VERSION 5.8 ;
BUSBITCHARS "[]" ;
DIVIDERCHAR "/" ;
UNITS
    DATABASE MICRONS 1000 ;
END UNITS

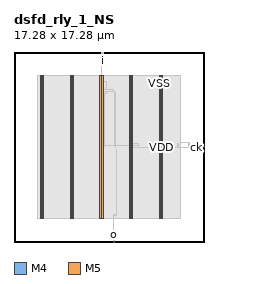
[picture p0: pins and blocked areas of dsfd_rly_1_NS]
MACRO dsfd_rly_1_NS
  FOREIGN dsfd_rly_1_NS 0 0 ;
  CLASS BLOCK ;
  SIZE 17.28 BY 17.28 ;
  PIN ck
    DIRECTION INPUT ;
    USE SIGNAL ;
    PORT
      LAYER M4 ;
        RECT  17.196 8.592 17.28 8.616 ;
    END
  END ck
  PIN i
    DIRECTION INPUT ;
    USE SIGNAL ;
    PORT
      LAYER M5 ;
        RECT  8.112 17.196 8.136 17.28 ;
    END
  END i
  PIN o
    DIRECTION OUTPUT ;
    USE SIGNAL ;
    PORT
      LAYER M5 ;
        RECT  9.072 0 9.096 0.084 ;
    END
  END o
  PIN rs
    DIRECTION INPUT ;
    USE SIGNAL ;
    PORT
      LAYER M4 ;
        RECT  17.196 8.688 17.28 8.712 ;
    END
  END rs
  PIN VDD
    DIRECTION INOUT ;
    USE POWER ;
    PORT
      LAYER M5 ;
        RECT  13.392 2.151 13.512 15.129 ;
        RECT  10.692 2.151 10.812 15.129 ;
        RECT  7.992 2.151 8.112 15.129 ;
        RECT  5.292 2.151 5.412 15.129 ;
        RECT  2.592 2.151 2.712 15.129 ;
    END
  END VDD
  PIN VSS
    DIRECTION INOUT ;
    USE GROUND ;
    PORT
      LAYER M5 ;
        RECT  13.2 2.137 13.32 15.143 ;
        RECT  10.5 2.137 10.62 15.143 ;
        RECT  7.8 2.137 7.92 15.143 ;
        RECT  5.1 2.137 5.22 15.143 ;
        RECT  2.4 2.137 2.52 15.143 ;
    END
  END VSS
  OBS
    LAYER RVTN ;
     RECT  2.16 2.16 15.12 2.295 ;
     RECT  2.16 2.565 15.12 2.835 ;
     RECT  2.16 3.105 15.12 3.375 ;
     RECT  2.16 3.645 15.12 3.915 ;
     RECT  2.16 4.185 15.12 4.455 ;
     RECT  2.16 4.725 15.12 4.995 ;
     RECT  2.16 5.265 15.12 5.535 ;
     RECT  2.16 5.805 15.12 6.075 ;
     RECT  2.16 6.345 15.12 6.615 ;
     RECT  2.16 6.885 15.12 7.155 ;
     RECT  2.16 7.425 15.12 7.695 ;
     RECT  2.16 7.965 15.12 8.235 ;
     RECT  2.16 8.505 15.12 8.775 ;
     RECT  2.16 9.045 15.12 9.315 ;
     RECT  2.16 9.585 15.12 9.855 ;
     RECT  2.16 10.125 15.12 10.395 ;
     RECT  2.16 10.665 15.12 10.935 ;
     RECT  2.16 11.205 15.12 11.475 ;
     RECT  2.16 11.745 15.12 12.015 ;
     RECT  2.16 12.285 15.12 12.555 ;
     RECT  2.16 12.825 15.12 13.095 ;
     RECT  2.16 13.365 15.12 13.635 ;
     RECT  2.16 13.905 15.12 14.175 ;
     RECT  2.16 14.445 15.12 14.715 ;
     RECT  2.16 14.985 15.12 15.12 ;
    LAYER RVTP ;
     RECT  2.16 2.295 15.12 2.565 ;
     RECT  2.16 2.835 15.12 3.105 ;
     RECT  2.16 3.375 15.12 3.645 ;
     RECT  2.16 3.915 15.12 4.185 ;
     RECT  2.16 4.455 15.12 4.725 ;
     RECT  2.16 4.995 15.12 5.265 ;
     RECT  2.16 5.535 15.12 5.805 ;
     RECT  2.16 6.075 15.12 6.345 ;
     RECT  2.16 6.615 15.12 6.885 ;
     RECT  2.16 7.155 15.12 7.425 ;
     RECT  2.16 7.695 15.12 7.965 ;
     RECT  2.16 8.235 15.12 8.505 ;
     RECT  2.16 8.775 15.12 9.045 ;
     RECT  2.16 9.315 15.12 9.585 ;
     RECT  2.16 9.855 15.12 10.125 ;
     RECT  2.16 10.395 15.12 10.665 ;
     RECT  2.16 10.935 15.12 11.205 ;
     RECT  2.16 11.475 15.12 11.745 ;
     RECT  2.16 12.015 15.12 12.285 ;
     RECT  2.16 12.555 15.12 12.825 ;
     RECT  2.16 13.095 15.12 13.365 ;
     RECT  2.16 13.635 15.12 13.905 ;
     RECT  2.16 14.175 15.12 14.445 ;
     RECT  2.16 14.715 15.12 14.985 ;
    LAYER M1 ;
     RECT  2.16 2.151 15.12 15.129 ;
    LAYER M2 ;
     RECT  2.16 2.151 15.12 15.129 ;
     RECT  15.12 9.018 15.935 9.036 ;
    LAYER M3 ;
     RECT  9.036 0.091 9.054 2.371 ;
     RECT  2.415 2.143 2.505 2.413 ;
     RECT  5.115 2.143 5.205 2.413 ;
     RECT  7.815 2.143 7.905 2.413 ;
     RECT  10.515 2.143 10.605 2.413 ;
     RECT  13.215 2.143 13.305 2.413 ;
     RECT  9.036 2.371 9.342 2.489 ;
     RECT  9.324 2.489 9.342 8.429 ;
     RECT  13.215 2.413 13.497 8.581 ;
     RECT  13.104 8.581 13.497 8.621 ;
     RECT  10.515 2.413 10.797 8.779 ;
     RECT  9.216 8.581 9.234 8.851 ;
     RECT  10.515 8.779 11.286 8.969 ;
     RECT  14.904 8.707 14.922 8.969 ;
     RECT  13.212 8.621 13.497 9.005 ;
     RECT  15.912 8.683 15.93 9.041 ;
     RECT  9.144 8.851 9.234 11.272 ;
     RECT  7.815 2.413 8.097 13.099 ;
     RECT  7.815 13.099 8.19 13.531 ;
     RECT  9.108 11.272 9.234 13.559 ;
     RECT  9.108 13.559 9.126 13.667 ;
     RECT  7.815 13.531 8.37 13.675 ;
     RECT  7.815 13.675 9.054 13.829 ;
     RECT  7.815 13.829 8.37 14.639 ;
     RECT  2.415 2.413 2.697 14.867 ;
     RECT  5.115 2.413 5.397 14.867 ;
     RECT  10.515 8.969 10.797 14.867 ;
     RECT  13.215 9.005 13.497 14.867 ;
     RECT  7.815 14.639 8.154 14.909 ;
     RECT  2.415 14.867 2.505 15.137 ;
     RECT  5.115 14.867 5.205 15.137 ;
     RECT  7.815 14.909 7.974 15.137 ;
     RECT  10.515 14.867 10.605 15.137 ;
     RECT  13.215 14.867 13.305 15.137 ;
     RECT  7.956 15.137 7.974 17.261 ;
    LAYER M4 ;
     RECT  2.408 2.148 2.512 15.132 ;
     RECT  2.512 2.418 2.704 14.862 ;
     RECT  5.108 2.148 5.212 15.132 ;
     RECT  5.212 2.418 5.404 14.862 ;
     RECT  7.808 2.148 7.912 15.132 ;
     RECT  7.944 17.232 8.005 17.256 ;
     RECT  8.005 17.136 8.064 17.256 ;
     RECT  7.912 2.418 8.104 14.862 ;
     RECT  8.064 17.136 8.147 17.16 ;
     RECT  8.104 13.104 8.245 13.128 ;
     RECT  9.025 0.096 9.109 0.12 ;
     RECT  8.104 8.736 10.508 8.76 ;
     RECT  10.508 2.148 10.612 15.132 ;
     RECT  10.612 2.418 10.804 14.862 ;
     RECT  10.804 8.592 13.208 8.616 ;
     RECT  13.208 2.148 13.312 15.132 ;
     RECT  13.312 2.418 13.504 14.862 ;
     RECT  13.504 8.592 15.901 8.616 ;
     RECT  15.901 8.592 17.244 8.712 ;
    LAYER M5 ;
     RECT  9.072 0.016 9.096 0.131 ;
     RECT  2.4 2.137 2.52 2.151 ;
     RECT  5.1 2.137 5.22 2.151 ;
     RECT  7.8 2.137 7.92 2.151 ;
     RECT  10.5 2.137 10.62 2.151 ;
     RECT  13.2 2.137 13.32 2.151 ;
     RECT  7.8 2.151 8.112 8.725 ;
     RECT  7.8 8.725 8.232 13.139 ;
     RECT  2.4 2.151 2.712 15.129 ;
     RECT  5.1 2.151 5.412 15.129 ;
     RECT  7.8 13.139 8.112 15.129 ;
     RECT  10.5 2.151 10.812 15.129 ;
     RECT  13.2 2.151 13.512 15.129 ;
     RECT  2.4 15.129 2.52 15.143 ;
     RECT  5.1 15.129 5.22 15.143 ;
     RECT  7.8 15.129 7.92 15.143 ;
     RECT  10.5 15.129 10.62 15.143 ;
     RECT  13.2 15.129 13.32 15.143 ;
     RECT  8.016 17.125 8.136 17.232 ;
     RECT  8.016 17.232 8.04 17.267 ;
  END
END dsfd_rly_1_NS
END LIBRARY
